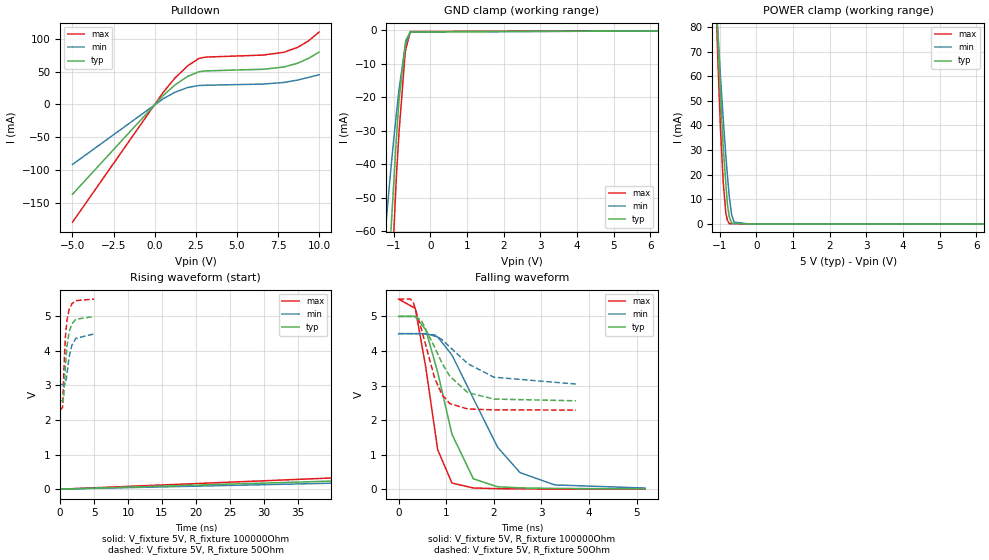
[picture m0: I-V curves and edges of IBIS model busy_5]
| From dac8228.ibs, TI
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|   busy_5 Model
[Model]   busy_5
Model_type   Open_drain
Polarity   Non-Inverting
Vmeas = 2.25
Vref = 5
Cref = 10pF
Rref = 100000
|   typ   min   max
|   (nom PVT)   (Fast PVT)   (slow PVT)
|C_comp from frequency method(F=50MHz)
|Average
C_comp   7.613e-12   6.267e-12   8.966e-12
|ON state : BUFFER OUTPUT TURNED LOW
|C_comp   7.719e-12   6.391e-12   9.083e-12
|OFF state: BUFFER IN HIGH IMPEDANCE
|C_comp   7.508e-12   6.143e-12   8.849e-12
|C_comp from L-C Tank method(L=1nH)
|Average
|C_comp   7.024e-12   5.919e-12   8.186e-12
|ON state : BUFFER OUTPUT TURNED LOW
|Resonant Frequency(Hz)   1.890e+09   2.050e+09   1.750e+09
|C_comp   7.098e-12   6.033e-12   8.279e-12
|OFF state: BUFFER IN HIGH IMPEDANCE
|Resonant Frequency(Hz)   1.910e+09   2.090e+09   1.770e+09
|C_comp   6.950e-12   5.805e-12   8.093e-12
| Where nom  PVT is Nominal Process,  5V,  33C
|   Fast PVT is Strong Process,   5.5V,  -40C
|   Slow PVT is Weak Process,   4.5V,  113C
[Voltage Range]   5   4.5   5.5
|Ambient Temperature   25   105   -40
|Junction Temperature
[Temperature Range]   33   113   -40
[Pullup Reference]   5   4.5   5.5
[Pulldown Reference]   0   0   0
[Power Clamp Reference]   5   4.5   5.5
[GND Clamp Reference]   0   0   0
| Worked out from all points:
|   slope of the pulldown table from 0 to 0.75 V, typ, clamps not added: 39.7 ohm
|   GND clamp passes 1 mA (typ) near -0.60 V on its own axis
|   POWER clamp passes 1 mA (typ) near -0.70 V on its own axis
|   falling waveform, V_fixture 5V, R_fixture 100000Ohm: 20-80 % time 545ps typ, 991ps min, 350ps max; typ from 5 V to 0.008 V
|   rising waveform, V_fixture 5V, R_fixture 100000Ohm: 20-80 % time 1.09us typ, 1.29us min, 888ns max; typ from 0.002 V to 4.98 V
|   falling waveform, V_fixture 5V, R_fixture 50Ohm: 20-80 % time 583ps typ, 809ps min, 402ps max; typ from 5 V to 2.56 V
|   rising waveform, V_fixture 5V, R_fixture 50Ohm: 20-80 % time 636ps typ, 800ps min, 515ps max; typ from 2.55 V to 5 V
[Pulldown]
|   Voltage   I(typ)   I(min)   I(max)
-5V       -136.5mA   -91.21mA   -178.9mA
528mV     13.89mA    8.876mA    18.73mA
1.221V    29.43mA    18.44mA    39.85mA
2.007V    42.76mA    25.78mA    58.81mA
2.684V    49.65mA    28.82mA    69.89mA
3.08V     51.01mA    29.23mA    71.98mA
6.6V      53.49mA    31mA       75.06mA
7.854V    56.91mA    33.43mA    79.28mA
8.684V    62.67mA    37.04mA    86.67mA
9.345V    69.89mA    41.09mA    96.42mA
10V       79.54mA    45.11mA    110mA
[GND Clamp]
|   Voltage   I(typ)   I(min)   I(max)
-5V       -981.7mA   -687.3mA   -1.357A
-1.368V   -120.3mA   -78.69mA   -173.2mA
-1.228V   -91.1mA    -60.29mA   -129.3mA
-1.14V    -72.57mA   -49.33mA   -102.3mA
-1.089V   -62.95mA   -43.03mA   -86.87mA
-1.001V   -46.36mA   -32.99mA   -61.99mA
-929.5mV  -33.02mA   -25.32mA   -44.54mA
-855mV    -20.97mA   -17.76mA   -30.72mA
-693mV    -5.221mA   -5.274mA   -7.735mA
-670mV    -2.985mA   -4.048mA   -5.704mA
-544.5mV  -503.3uA   -473.7uA   -353.4uA
10V       0A         0A         0A
[POWER Clamp]
|   Voltage   I(typ)   I(min)   I(max)
-5V       1.399A     1.179A     1.687A
-1.111V   95.69mA    93.54mA    92.87mA
-1.056V   76.86mA    79.04mA    67.78mA
-984.5mV  52.94mA    60.5mA     39.43mA
-907.5mV  31.53mA    42.75mA    16.99mA
-836mV    16.41mA    27.83mA    4.45mA
-795mV    8.276mA    20.19mA    1.601mA
-742.5mV  2.885mA    11.14mA    115.5uA
-679.5mV  421.1uA    3.912mA    105.7uA
-612mV    201.1uA    759.8uA    95.21uA
-202.5mV  26.43nA    5.18nA     31.5uA
10V       0A         0A         0A
[Ramp]
R_load = 100000
|   typ   min   max
dV/dt_r   2.9977/1.09783e-06   2.69544/1.31745e-06   3.29874/8.92645e-07
dV/dt_f   2.99891/5.49879e-10   2.69849/1.00519e-09   3.2991/3.57406e-10
[Falling Waveform]
V_fixture = 5V
V_fixture_min = 4.5V
V_fixture_max = 5.5V
R_fixture = 100000Ohm
|   Time   V(typ)   V(min)   V(max)
0s        5V         4.5V       5.5V
350ps     5.003V     4.5V       5.232V
570ps     4.61V      4.502V     3.525V
820ps     3.385V     4.406V     1.141V
1.12ns    1.592V     3.883V     179.2mV
1.57ns    299.8mV    2.624V     35.44mV
2.08ns    70.83mV    1.212V     16.27mV
2.55ns    39.48mV    479.9mV    9.502mV
3.28ns    23.31mV    124.6mV    4.571mV
5.18ns    8.48mV     34.14mV    1.684mV
[Rising Waveform]
V_fixture = 5V
V_fixture_min = 4.5V
V_fixture_max = 5.5V
R_fixture = 100000Ohm
|   Time   V(typ)   V(min)   V(max)
0s        1.778mV    2.466mV    1.463mV
150.8ns   881mV      648mV      1.22V
263.1ns   1.467V     1.101V     1.969V
507.8ns   2.46V      1.914V     3.135V
688.7ns   2.988V     2.379V     3.71V
885.5ns   3.425V     2.779V     4.158V
1.304us   4.036V     3.376V     4.737V
1.857us   4.468V     3.834V     5.113V
2.706us   4.769V     4.183V     5.351V
5.373us   4.98V      4.462V     5.491V
[Falling Waveform]
V_fixture = 5V
V_fixture_min = 4.5V
V_fixture_max = 5.5V
R_fixture = 50Ohm
|   Time   V(typ)   V(min)   V(max)
0s        5V         4.5V       5.5V
247ps     5V         4.5V       5.502V
310ps     5.001V     4.5V       5.397V
469ps     4.906V     4.5V       4.679V
759ps     4.097V     4.464V     3.2V
914ps     3.642V     4.323V     2.734V
1.073ns   3.273V     4.119V     2.479V
1.451ns   2.796V     3.634V     2.321V
2ns       2.608V     3.241V     2.296V
3.724ns   2.559V     3.043V     2.29V
[Rising Waveform]
V_fixture = 5V
V_fixture_min = 4.5V
V_fixture_max = 5.5V
R_fixture = 50Ohm
|   Time   V(typ)   V(min)   V(max)
0s        2.554V     3.029V     2.289V
356ps     2.551V     3.029V     2.364V
425ps     2.559V     3.028V     2.642V
541ps     2.704V     3.026V     3.402V
766ps     3.518V     3.051V     4.389V
1.004ns   4.135V     3.328V     4.886V
1.318ns   4.544V     3.822V     5.19V
1.726ns   4.78V      4.162V     5.362V
2.312ns   4.913V     4.362V     5.454V
4.999ns   4.996V     4.492V     5.499V
